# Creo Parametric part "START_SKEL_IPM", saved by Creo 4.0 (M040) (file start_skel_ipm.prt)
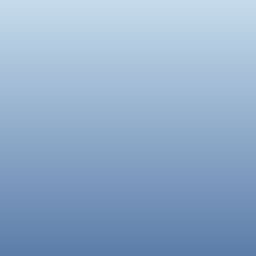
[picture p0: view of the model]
Units: IPM (mmkgsecC); MM, KILOGRAM, SECS

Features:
  1. datum plane "SKEL_BOKORYS"
  2. datum plane "SKEL_PODORYS"
  3. datum plane "SKEL_NARYS"
  4. coordinate system

Other named items: SKEL_KS

Layers: 01_STD_KSYS, 02_STD_ROVINY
